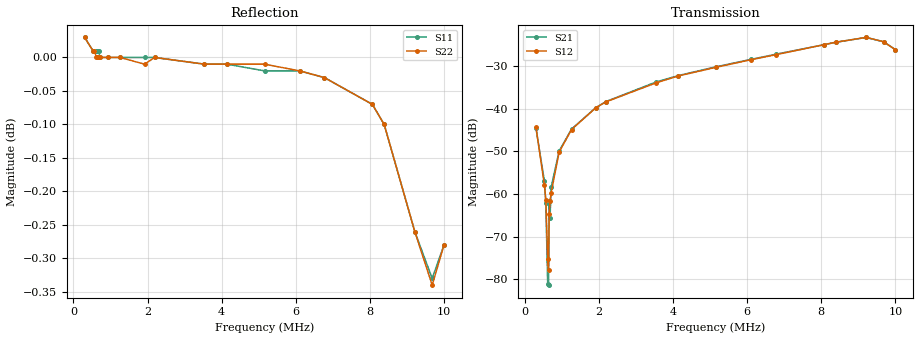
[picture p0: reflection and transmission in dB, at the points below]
!s-Parameter Generated by FASTRON Sdn. Bhd.
!FASTRON P/N : 1812AFTC-722X
!Keysight Technologies: E5071C_MY46733604_B.14.02
!Date: Wed Mar 18 14:05:07 2026
!Version  :Rev00  Wed Mar 18 14:05:07 2026
!Data & Calibration Information:
!Freq  S11:SOLT2(ON)  S21:SOLT2(ON)  S12:SOLT2(ON)  S22:SOLT2(ON)
!PortZ  Port1:50+j0  Port2:50+j0
!When reading reference impedance value at option line is always used.
! Remarks : This data is being provided solely for informational purposes.
# Hz S dB R 50
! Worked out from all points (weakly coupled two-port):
!   1601 points, 300 kHz to 10 MHz, reference 50 ohm
!   highest |S21| = -23.26 dB at 9.211 MHz (marker M1); lowest = -81.4 dB at 639.4 kHz (marker M2)
!   lowest |S11| = -0.3 dB at 9.681 MHz (marker M3), VSWR 51.91, Z = 9.04 - j145 ohm
!   |S11| at or under -10 dB: nowhere
!   |S22| runs from -0.3 to 0.0 dB; largest |S21 - S12| = 0.00089
!   S11 on the Smith chart (normalised r, x): 300 kHz: -0, +11; 2.19 MHz: 0.00, +1.36; 4.144 MHz: 0.00, +0.39; 6.102 MHz: 0.00, -0.20; 8.066 MHz: 0.01, -0.96; 10 MHz: 0.30, -4.18
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300000  0.03 10.1  -44.49 -89.2  -44.28 -89.1  0.03 -11.0
527037  0.01 17.6  -56.83 -81.8  -57.81 -79.0  0.01 -19.5
566426  0.01 18.8  -61.97 -60.5  -61.37 -71.0  0.01 -21.0
617461  0.01 20.5  -81.14 -49.9  -75.27 -19.8  0.00 -22.8
639429  0.01 21.2  -81.35 -10.4  -77.86 19.7  0.00 -23.7
657003  0.01 21.8  -61.66 71.8  -64.62 63.0  0.00 -24.3
680434  0.01 22.6  -65.53 99.5  -61.56 86.4  0.00 -25.2
711189  0.00 23.6  -58.34 82.1  -59.67 82.3  0.00 -26.3
926769  0.00 30.8  -49.89 84.1  -50.14 85.3  -0.00 -34.3
1259826  -0.00 41.8  -44.75 84.5  -44.87 85.0  -0.00 -46.6
1917564  -0.00 63.7  -39.71 84.0  -39.73 84.2  -0.01 -71.0
2189863  -0.00 72.7  -38.29 83.4  -38.36 84.3  -0.00 -81.0
3534704  -0.01 117.4  -33.73 81.5  -33.93 81.1  -0.01 -130.8
4143721  -0.01 137.6  -32.19 80.0  -32.28 80.2  -0.01 -153.4
5155786  -0.02 171.2  -30.15 78.0  -30.27 78.1  -0.01 169.1
6101602  -0.02 -157.5  -28.40 75.9  -28.48 75.8  -0.02 134.1
6770355  -0.03 -135.4  -27.20 73.8  -27.31 74.0  -0.03 109.3
8066168  -0.07 -92.6  -24.97 67.1  -24.97 67.1  -0.07 61.0
8385344  -0.10 -82.1  -24.40 64.0  -24.38 64.1  -0.10 49.1
9211447  -0.26 -54.6  -23.26 48.4  -23.24 48.4  -0.26 18.6
9680824  -0.33 -38.0  -24.27 35.3  -24.25 35.3  -0.34 2.2
1e7  -0.28 -26.8  -26.12 33.8  -26.11 33.8  -0.28 -8.9
